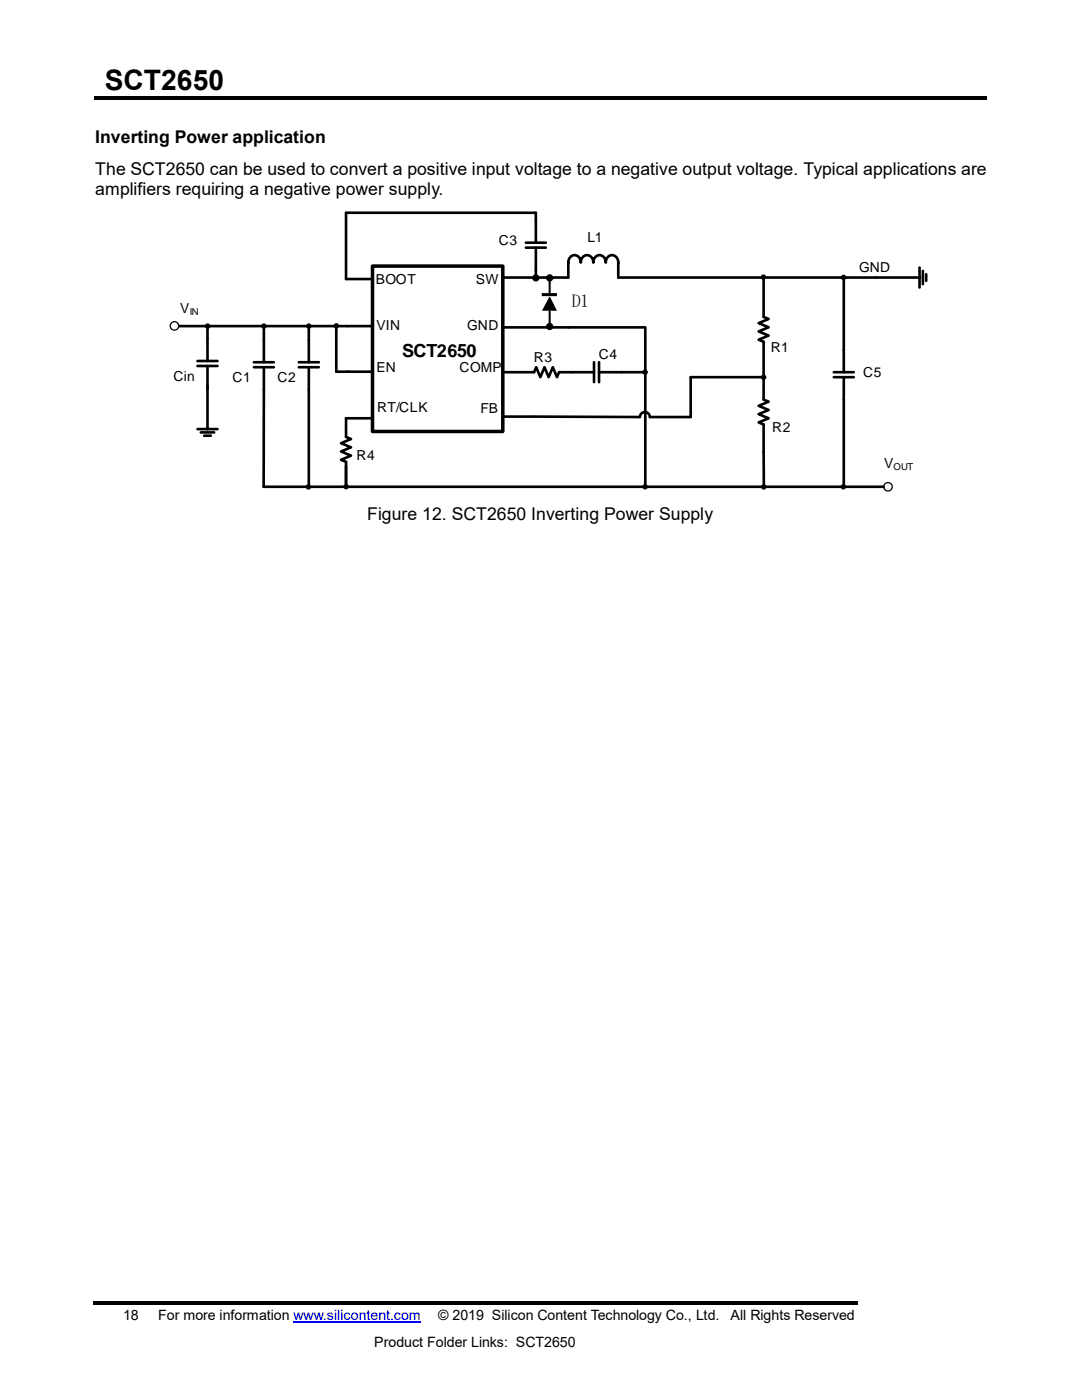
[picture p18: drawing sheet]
<svg xmlns="http://www.w3.org/2000/svg" width="216mm" height="279mm" viewBox="0 0 216 279" stroke-linecap="round" stroke-linejoin="round" font-family="sans-serif">
<defs><g id="words">
<text font-size="5.6" x="20.9" y="17.9">SCT2650</text>
<g font-size="3.6">
<text x="114.1" y="61.3">D1</text>
<text x="80.2" y="71.2">SCT2650</text>
</g>
<g font-size="3.5">
<text x="19" y="28.6">Inverting Power application</text>
<text x="19" y="34.8">The SCT2650 can be used to convert a positive input voltage to a negative output voltage. Typical applications are</text>
<text x="19" y="38.9">amplifiers requiring a negative power supply.</text>
<text x="73.3" y="103.8">Figure 12. SCT2650 Inverting Power Supply</text>
</g>
<g font-size="2.8">
<text x="75" y="56.8">BOOT</text>
<text x="94.9" y="56.8">SW</text>
<text x="36" y="62.5">V</text>
<text x="46.4" y="76.2">C1</text>
<text x="55.4" y="76.2">C2</text>
<text x="75.2" y="82.1">RT/CLK</text>
<text x="176.4" y="93.3">V</text>
<text x="24.6" y="263.4">18</text>
<text x="31.6" y="263.4">For more information www.silicontent.com</text>
<text x="87.4" y="263.4">© 2019 Silicon Content Technology Co., Ltd.</text>
<text x="145.8" y="263.4">All Rights Reserved</text>
<text x="74.7" y="268.8">Product Folder Links: SCT2650</text>
</g>
<g font-size="2.7">
<text x="99.5" y="48.8">C3</text>
<text x="117.2" y="48.3">L1</text>
<text x="171.4" y="54.3">GND</text>
<text x="75.1" y="65.8">VIN</text>
<text x="93.2" y="65.8">GND</text>
<text x="119.5" y="71.7">C4</text>
<text x="153.8" y="70.3">R1</text>
<text x="34.6" y="76">Cin</text>
<text x="75.1" y="74.2">EN</text>
<text x="91.7" y="74.2">COMP</text>
<text x="106.5" y="72.3">R3</text>
<text x="172.2" y="75.3">C5</text>
<text x="95.9" y="82.4">FB</text>
<text x="154.1" y="86.2">R2</text>
<text x="71.2" y="91.8">R4</text>
</g>
<g font-size="1.9">
<text x="37.9" y="62.9">IN</text>
<text x="178.3" y="93.7">OUT</text>
</g>
</g></defs>
<g fill="#000">
<path d="M18.8 19.2h178v.8h-178z" fill-rule="evenodd"/>
<path d="M18.5 259.7h152.6v.7h-152.6z" fill-rule="evenodd"/>
</g>
<path d="M58.6 263.8h25.4" fill="none" stroke="#00f" stroke-width=".21"/>
<g fill="none" stroke="#000" stroke-width=".53">
<path d="M104.9 49.4h4M104.9 48.4h4M106.9 48.4v-5.9h-37.9v13.2h5.3M106.9 49.4v4.5M113.4 55.4v-3a1.27 1.27 0 0 1 1.2-1.5 1.27 1.27 0 0 1 1.3 1.5 1.26 1.26 0 0 1 1.2-1.5 1.26 1.26 0 0 1 1.3 1.5 1.27 1.27 0 0 1 1.2-1.5 1.27 1.27 0 0 1 1.3 1.5 1.27 1.27 0 0 1 1.2-1.5 1.27 1.27 0 0 1 1.3 1.5v3h60.1M152.4 55.5v7.7l1 .5-2 .8 2 .8-2 .8 2 .9-2 .8 1 .4v11.5l1 .5-2 .8 2 .8-2 .8 2 .9-2 .8 1 .4v5.5M183.5 53.4v4M184.1 54.1v2.6M184.8 54.7v1.4M35.7 65.1h38.6M69.3 74.2h5M100.2 74.3h6.4l.4-1 .8 2 .8-2 .9 2 .8-2 .8 2 .5-1"/>
<path d="M114 74.3h4.5M118.5 72.3v4M119.5 74.3h4.5M119.5 72.3v4M166.4 75.3h4M166.4 74.3h4M168.4 69.8v4.5M168.4 75.3v4.4M69 93v3.5M74.3 83.5h-5.3v3.7"/>
</g>
<path d="M74.3 53.1h26v33h-26z" fill="none" stroke="#000" stroke-width=".7"/>
<circle cx="177.2" cy="97.1" r=".85" fill="#fff"/>
<circle cx="177.2" cy="97.1" r=".85" fill="none" stroke="#000" stroke-width=".25"/>
<circle cx="34.8" cy="65" r=".85" fill="#fff"/>
<g fill="none" stroke="#000" stroke-width=".25">
<circle cx="152.3" cy="55.3" r=".42"/>
<circle cx="168.3" cy="55.4" r=".42"/>
<circle cx="34.8" cy="65" r=".85"/>
<circle cx="41.4" cy="65.1" r=".42"/>
<circle cx="52.7" cy="65.1" r=".42"/>
<circle cx="61.6" cy="65.1" r=".42"/>
<circle cx="67.1" cy="65" r=".42"/>
<circle cx="128.7" cy="74.3" r=".42"/>
<circle cx="152.4" cy="75.3" r=".42"/>
<circle cx="61.5" cy="97.2" r=".42"/>
<circle cx="69.1" cy="97.1" r=".42"/>
<circle cx="128.7" cy="97.1" r=".42"/>
<circle cx="152.4" cy="97.2" r=".42"/>
<circle cx="168.3" cy="97.1" r=".42"/>
</g>
<g fill="none" stroke="#000" stroke-width=".53">
<path d="M100.4 55.4h13M106.9 53.9v1.5M168.4 55.4v14.4M39.4 73h4M39.4 72h4M41.4 65.1v6.9M41.4 73v12.6M50.7 73.3h3.9M50.7 72.3h3.9M52.7 73.3l-.1 23.8h76.2v-22.8M52.7 65.1v7.2M59.6 73.3h4"/>
<path d="M59.6 72.3h4M61.6 65.1v7.2M61.6 73.3v23.8M67.1 65.2v9h2.3M100.3 65.3h28.5v9h-4.8M111.6 74.3h2.4M152.3 75.3h-14.5v7.9h-8.1a1 1 0 0 0-1-1 1 1 0 0 0-1 1l-21.2-.1M168.4 79.7v17.4M39.4 85.6h4M40.1 86.3h2.6M40.7 87h1.4M69 87.2l1 .4-2 .8 2 .9-2 .8 2 .8-2 .9 1 .4v4.9"/>
<path d="M100.4 83.1h6M128.8 97.1h47.5M152.4 90.2v6.9"/>
</g>
<g fill="#000">
<path d="M108.1 58.5h3v.6h-3zM109.7 59.1l-1.6 2.9h3z" fill-rule="evenodd"/>
<circle cx="106.9" cy="55.5" r=".42"/>
<circle cx="109.7" cy="55.5" r=".42"/>
<circle cx="152.3" cy="55.3" r=".42"/>
<circle cx="168.3" cy="55.4" r=".42"/>
<circle cx="41.4" cy="65.1" r=".42"/>
<circle cx="52.7" cy="65.1" r=".42"/>
<circle cx="61.6" cy="65.1" r=".42"/>
<circle cx="67.1" cy="65" r=".42"/>
<circle cx="109.7" cy="65.2" r=".42"/>
<circle cx="128.7" cy="74.3" r=".42"/>
<circle cx="152.4" cy="75.3" r=".42"/>
<circle cx="61.5" cy="97.2" r=".42"/>
<circle cx="69.1" cy="97.1" r=".42"/>
<circle cx="128.7" cy="97.1" r=".42"/>
<circle cx="152.4" cy="97.2" r=".42"/>
<circle cx="168.3" cy="97.1" r=".42"/>
</g>
<g fill="none" stroke="#000" stroke-width=".61">
<circle cx="106.9" cy="55.5" r=".42"/>
<circle cx="109.7" cy="55.5" r=".42"/>
<circle cx="109.7" cy="65.2" r=".42"/>
</g>
<path d="M109.5 55h.4v3.5h-.4zM109.5 62h.4v3.2h-.4z" fill="#000"/>
<use href="#words"/>
</svg>
